VERSION 5.8 ;
BUSBITCHARS "[]" ;
DIVIDERCHAR "/" ;
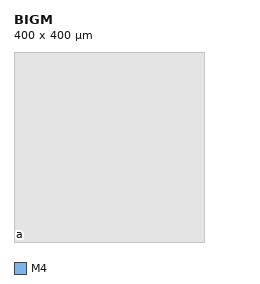
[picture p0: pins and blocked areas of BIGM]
MACRO BIGM
  CLASS BLOCK ;
  ORIGIN 0 0 ;
  SIZE 400 BY 400 ;
  PIN a
    DIRECTION INPUT ;
    USE SIGNAL ;
    PORT
      LAYER M4 ;
        RECT 0 7 0.5 7.1 ;
    END
  END a
  OBS
    LAYER M1 ;
      RECT 0 0 400 400 ;
    LAYER M2 ;
      RECT 0 0 400 400 ;
    LAYER M3 ;
      RECT 0 0 400 400 ;
  END
END BIGM
